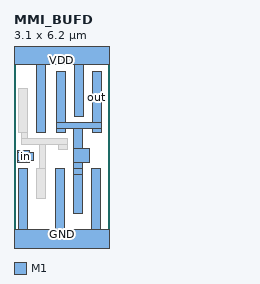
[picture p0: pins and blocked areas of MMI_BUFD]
MACRO MMI_BUFD
	CLASS CORE ;
	FOREIGN MMI_BUFD 0 0 ;
	SIZE 3.1 BY 6.2 ;
	SYMMETRY X Y ;
	SITE CORE1 ;
	PIN out
		DIRECTION output ;
		USE SIGNAL ;
		PORT
			LAYER M1 ;
			RECT 1.385 3.885 1.665 5.56 ;
			LAYER M1 ;
			RECT 2.565 3.885 2.845 5.56 ;
			LAYER M1 ;
			RECT 1.385 3.695 2.845 3.885 ;
			LAYER M1 ;
			RECT 1.385 3.575 1.665 3.695 ;
			LAYER M1 ;
			RECT 1.955 3.05 2.235 3.695 ;
			LAYER M1 ;
			RECT 2.565 3.575 2.845 3.695 ;
			LAYER M1 ;
			RECT 1.955 2.6 2.45 3.05 ;
			LAYER M1 ;
			RECT 1.955 2.395 2.235 2.6 ;
			LAYER M1 ;
			RECT 1.95 2.205 2.235 2.395 ;
			LAYER M1 ;
			RECT 1.95 0.925 2.23 2.205 ;
		END
		AntennaDiffArea 2.393525 ;
	END out
	PIN GND
		DIRECTION inout ;
		USE GROUND ;
		PORT
			LAYER M1 ;
			RECT 0.16 0.42 0.44 2.395 ;
			LAYER M1 ;
			RECT 1.36 0.42 1.64 2.395 ;
			LAYER M1 ;
			RECT 2.54 0.42 2.82 2.395 ;
			LAYER M1 ;
			RECT 0 -0.42 3.1 0.42 ;
		END
	END GND
	PIN VDD
		DIRECTION inout ;
		USE POWER ;
		PORT
			LAYER M1 ;
			RECT 0 5.78 3.1 6.62 ;
			LAYER M1 ;
			RECT 0.75 3.575 1.03 5.78 ;
			LAYER M1 ;
			RECT 1.975 4.105 2.255 5.78 ;
		END
	END VDD
	PIN in
		DIRECTION input ;
		USE SIGNAL ;
		PORT
			LAYER M1 ;
			RECT 0.12 2.93 0.5 2.98 ;
			LAYER M1 ;
			RECT 0.12 2.65 0.635 2.93 ;
			LAYER M1 ;
			RECT 0.12 2.6 0.5 2.65 ;
		END
		AntennaGateArea 0.468 ;
	END in
	OBS
		LAYER M1 ;
		RECT 0.16 3.575 0.44 5.025 ;
		LAYER M1 ;
		RECT 0.245 3.375 0.435 3.575 ;
		LAYER M1 ;
		RECT 0.245 3.18 1.745 3.375 ;
		LAYER M1 ;
		RECT 0.84 2.395 1.03 3.18 ;
		LAYER M1 ;
		RECT 1.465 3.015 1.745 3.18 ;
		LAYER M1 ;
		RECT 0.75 1.425 1.03 2.395 ;
	END
END MMI_BUFD
